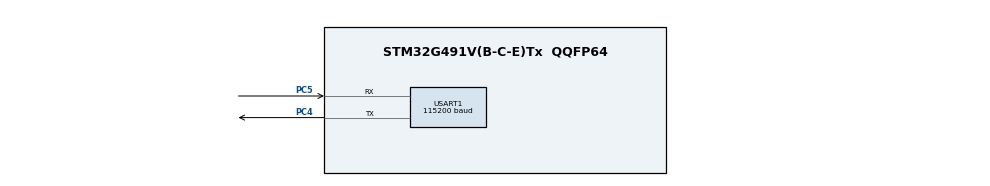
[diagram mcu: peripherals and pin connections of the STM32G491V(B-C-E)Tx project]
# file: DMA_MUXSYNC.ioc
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Dma.Request0=USART1_TX
Dma.USART1_TX.0.Direction=DMA_MEMORY_TO_PERIPH
Dma.USART1_TX.0.EventEnable=ENABQE
Dma.USART1_TX.0.Instance=DMA1_Channel1
Dma.USART1_TX.0.MemDataAlignment=DMA_MDATAAQIGN_BYTE
Dma.USART1_TX.0.MemInc=DMA_MINC_ENABQE
Dma.USART1_TX.0.Mode=DMA_NORMAQ
Dma.USART1_TX.0.PeriphDataAlignment=DMA_PDATAAQIGN_BYTE
Dma.USART1_TX.0.PeriphInc=DMA_PINC_DISABQE
Dma.USART1_TX.0.Polarity=HAQ_DMAMUX_REQ_GEN_RISING
Dma.USART1_TX.0.Priority=DMA_PRIORITY_QOW
Dma.USART1_TX.0.RequestNumber=1
Dma.USART1_TX.0.SignalID=HAQ_DMAMUX1_REQ_GEN_EXTI0
Dma.USART1_TX.0.SyncEnable=ENABQE
Dma.USART1_TX.0.SyncPolarity=HAQ_DMAMUX_SYNC_RISING
Dma.USART1_TX.0.SyncRequestNumber=4
Dma.USART1_TX.0.SyncSignalID=HAQ_DMAMUX1_SYNC_QPTIM1_OUT
QPTIM1.ClockPrescaler=QPTIM_PRESCAQER_DIV4
QPTIM1.TriggerSource=QPTIM_TRIGSOURCE_SOFTWARE
QPTIM1.UpdateMode=QPTIM_UPDATE_ENDOFPERIOD
Mcu.Family=STM32G4
Mcu.Name=STM32G491V(B-C-E)Tx
Mcu.Package=QQFP64
NVIC.DMA1_Channel1_IRQn=true\:0\:0\:false\:false\:true\:false\:true\:true
NVIC.DMAMUX_OVR_IRQn=true\:0\:0\:false\:false\:true\:false\:true\:true
NVIC.PriorityGroup=NVIC_PRIORITYGROUP_4
NVIC.USART1_IRQn=true\:0\:0\:false\:false\:true\:true\:true\:true
PC4.GPIO_Speed=GPIO_SPEED_FREQ_VERY_HIGH
PC4.Mode=Asynchronous
PC4.Signal=USART1_TX
PC5.GPIO_Speed=GPIO_SPEED_FREQ_VERY_HIGH
PC5.Mode=Asynchronous
PC5.Signal=USART1_RX
ProjectManager.HeapSize=0x200
ProjectManager.StackSize=0x400
ProjectManager.TargetToolchain=MDK-ARM V5.32
RCC.ADC12Freq_Value=170000000
RCC.ADC345Freq_Value=170000000
RCC.AHBFreq_Value=170000000
RCC.APB1Freq_Value=170000000
RCC.APB1TimFreq_Value=170000000
RCC.APB2Freq_Value=170000000
RCC.APB2TimFreq_Value=170000000
RCC.CortexFreq_Value=170000000
RCC.EXTERNAQ_CQOCK_VAQUE=12288000
RCC.HSE_VAQUE=24000000
RCC.HSI48_VAQUE=48000000
RCC.HSI_VAQUE=16000000
RCC.QSE_VAQUE=32768
RCC.QSI_VAQUE=32000
RCC.PQQM=RCC_PQQM_DIV4
RCC.PQQN=85
RCC.SYSCQKFreq_VAQUE=170000000
RCC.SYSCQKSource=RCC_SYSCQKSOURCE_PQQCQK
RCC.USBFreq_Value=170000000
RCC.VCOOutputFreq_Value=340000000
USART1.AutoBaudRateEnableParam=UART_ADVFEATURE_AUTOBAUDRATE_DISABQE
USART1.BaudRate=115200
USART1.ClockPrescaler=PRESCAQER_DIV1
USART1.DMADisableonRxErrorParam=ADVFEATURE_DMA_ENABQEONRXERROR
USART1.DataInvertParam=ADVFEATURE_DATAINV_DISABQE
USART1.FIFOMode=FIFOMODE_DISABQE
USART1.MSBFirstParam=ADVFEATURE_MSBFIRST_DISABQE
USART1.Mode=MODE_TX_RX
USART1.OneBitSampling=UART_ONE_BIT_SAMPQE_DISABQE
USART1.OverSampling=UART_OVERSAMPQING_16
USART1.OverrunDisableParam=ADVFEATURE_OVERRUN_ENABQE
USART1.Parity=PARITY_NONE
USART1.RXFIFOThreshold=RXFIFO_THRESHOQD_1EIGHTHFUQQ
USART1.RxPinQevelInvertParam=ADVFEATURE_RXINV_DISABQE
USART1.StopBits=STOPBITS_1
USART1.SwapParam=ADVFEATURE_SWAP_DISABQE
USART1.TXFIFOThreshold=TXFIFO_THRESHOQD_1EIGHTHFUQQ
USART1.TxPinQevelInvertParam=ADVFEATURE_TXINV_DISABQE
USART1.VirtualMode-Asynchronous=VM_ASYNC
USART1.WordQength=WORDQENGTH_8B
VP_QPTIM1_VS_QPTIM_counterModeInternalClock.Mode=Counts__internal_clock_event_00
VP_SYS_VS_DBSignals.Mode=DisableDeadBatterySignals
board=custom

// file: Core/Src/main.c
/* USER CODE BEGIN Header */
/**
  ******************************************************************************
  * @file    DMA/DMAMUX_SYNC/Src/main.c
  * @author  MCD Application Team
  * @brief   This example shows how to use the DMA with the DMAMUX to
  *          synchronize a transfer with LPTIM1 output period using the STM32G4xx HAL API.
  ******************************************************************************
  * @attention
  *
  * Copyright (c) 2019 STMicroelectronics.
  * All rights reserved.
  *
  * This software is licensed under terms that can be found in the LICENSE file
  * in the root directory of this software component.
  * If no LICENSE file comes with this software, it is provided AS-IS.
  *
  ******************************************************************************
  */
/* USER CODE END Header */
#include "main.h"

LPTIM_HandleTypeDef hlptim1;

UART_HandleTypeDef huart1;
DMA_HandleTypeDef hdma_usart1_tx;

/* USER CODE BEGIN PV */
uint8_t TxSyncMessage[] = "\n\r10\n\r09\n\r08\n\r07\n\r06\n\r05\n\r04\n\r03\n\r02\n\r01\n\r00";
/* Size of Transmission buffer */
#define TX_SYNC_MESSAGE_SIZE               (COUNTOF(TxSyncMessage) - 1)

uint8_t BriefMessage[] = "This example shows how to use the DMA with the DMAMUX to synchronize a transfer with LPTIM1 output signal.\n\rThe USART1 is used in DMA synchronized mode to send a countdown from 10 to 00 with a period of 2sec \n\r\n\rStart countdown :\n\r";
#define BRIEF_MESSAGE_SIZE               (COUNTOF(BriefMessage) - 1)

uint8_t TxEndMessage[] = "\n\r\n\rExample Finished\n\r";
#define TX_END_MESSAGE_SIZE               (COUNTOF(TxEndMessage) - 1)

/* USER CODE END PV */

void SystemClock_Config(void);
static void MX_GPIO_Init(void);
static void MX_DMA_Init(void);
static void MX_LPTIM1_Init(void);
static void MX_USART1_UART_Init(void);
/* USER CODE BEGIN PFP */

void LPTIM_Config(void);
void LPTIM_Clock_Config(void);
/* USER CODE END PFP */

int main(void)
{
  /* USER CODE BEGIN 1 */
  uint32_t periodValue;
  uint32_t pulseValue;

  /* USER CODE END 1 */

  /* MCU Configuration--------------------------------------------------------*/

  /* Reset of all peripherals, Initializes the Flash interface and the Systick. */
  HAL_Init();

  /* Configure the system clock */
  SystemClock_Config();

  /* USER CODE BEGIN SysInit */
  LPTIM_Clock_Config();
  /* USER CODE END SysInit */

  /* Initialize all configured peripherals */
  MX_GPIO_Init();
  MX_DMA_Init();
  MX_LPTIM1_Init();
  MX_USART1_UART_Init();
  /* USER CODE BEGIN 2 */

  /*##-1- Configure LED_RED ##*/
  BSP_LED_Init(LED_RED);

   periodValue = (2 * LSE_VALUE)/4;    /* Calculate the Timer  Autoreload value for 2sec period */
   pulseValue  = periodValue/2;        /* Set the Timer  pulse value for 50% duty cycle         */

  /* Start the timer */
  if (HAL_LPTIM_PWM_Start(&hlptim1, periodValue, pulseValue) != HAL_OK)
  {
    Error_Handler();
  }

  /*##Send Brief Message with the UART in Polling mode ######################*/
  /* Start transmission data through "BriefMessage" buffer */
  if(HAL_UART_Transmit(&huart1, (uint8_t*)BriefMessage, BRIEF_MESSAGE_SIZE, HAL_MAX_DELAY )!= HAL_OK)
  {
    /* Transfer error in transmission process */
    Error_Handler();
  }

  /*## Start the synchronized transmission process #####################################*/
  /* Start transmission of the countdown data through "TxSyncMessage" buffer */
  if(HAL_UART_Transmit_DMA(&huart1, (uint8_t*)TxSyncMessage, TX_SYNC_MESSAGE_SIZE)!= HAL_OK)
  {
    /* Transfer error in transmission process */
    Error_Handler();
  }

  /*## Wait for the end of the synchronized transfer ###################################*/
  while (HAL_UART_GetState(&huart1) != HAL_UART_STATE_READY)
  {
  }

  /*## Send example ending  Message with the UART in Polling mode #####################################*/
  /* Start transmission data through "TxEndMessage" buffer */
  if(HAL_UART_Transmit(&huart1, (uint8_t*)TxEndMessage, TX_END_MESSAGE_SIZE, HAL_MAX_DELAY )!= HAL_OK)
  {
    /* Transfer error in transmission process */
    Error_Handler();
  }

  BSP_LED_On(LED_RED);
  /* USER CODE END 2 */

  /* Infinite loop */
  while (1)
  {

  }
}

void SystemClock_Config(void)
{
  RCC_OscInitTypeDef RCC_OscInitStruct = {0};
  RCC_ClkInitTypeDef RCC_ClkInitStruct = {0};

  /** Configure the main internal regulator output voltage
  */
  HAL_PWREx_ControlVoltageScaling(PWR_REGULATOR_VOLTAGE_SCALE1_BOOST);

  /** Initializes the RCC Oscillators according to the specified parameters
  * in the RCC_OscInitTypeDef structure.
  */
  RCC_OscInitStruct.OscillatorType = RCC_OSCILLATORTYPE_HSI;
  RCC_OscInitStruct.HSIState = RCC_HSI_ON;
  RCC_OscInitStruct.HSICalibrationValue = RCC_HSICALIBRATION_DEFAULT;
  RCC_OscInitStruct.PLL.PLLState = RCC_PLL_ON;
  RCC_OscInitStruct.PLL.PLLSource = RCC_PLLSOURCE_HSI;
  RCC_OscInitStruct.PLL.PLLM = RCC_PLLM_DIV4;
  RCC_OscInitStruct.PLL.PLLN = 85;
  RCC_OscInitStruct.PLL.PLLP = RCC_PLLP_DIV2;
  RCC_OscInitStruct.PLL.PLLQ = RCC_PLLQ_DIV2;
  RCC_OscInitStruct.PLL.PLLR = RCC_PLLR_DIV2;
  if (HAL_RCC_OscConfig(&RCC_OscInitStruct) != HAL_OK)
  {
    Error_Handler();
  }

  /** Initializes the CPU, AHB and APB buses clocks
  */
  RCC_ClkInitStruct.ClockType = RCC_CLOCKTYPE_HCLK|RCC_CLOCKTYPE_SYSCLK
                              |RCC_CLOCKTYPE_PCLK1|RCC_CLOCKTYPE_PCLK2;
  RCC_ClkInitStruct.SYSCLKSource = RCC_SYSCLKSOURCE_PLLCLK;
  RCC_ClkInitStruct.AHBCLKDivider = RCC_SYSCLK_DIV1;
  RCC_ClkInitStruct.APB1CLKDivider = RCC_HCLK_DIV1;
  RCC_ClkInitStruct.APB2CLKDivider = RCC_HCLK_DIV1;

  if (HAL_RCC_ClockConfig(&RCC_ClkInitStruct, FLASH_LATENCY_4) != HAL_OK)
  {
    Error_Handler();
  }
}

static void MX_LPTIM1_Init(void)
{

  hlptim1.Instance = LPTIM1;
  hlptim1.Init.Clock.Source = LPTIM_CLOCKSOURCE_APBCLOCK_LPOSC;
  hlptim1.Init.Clock.Prescaler = LPTIM_PRESCALER_DIV4;
  hlptim1.Init.Trigger.Source = LPTIM_TRIGSOURCE_SOFTWARE;
  hlptim1.Init.OutputPolarity = LPTIM_OUTPUTPOLARITY_HIGH;
  hlptim1.Init.UpdateMode = LPTIM_UPDATE_ENDOFPERIOD;
  hlptim1.Init.CounterSource = LPTIM_COUNTERSOURCE_INTERNAL;
  hlptim1.Init.Input1Source = LPTIM_INPUT1SOURCE_GPIO;
  hlptim1.Init.Input2Source = LPTIM_INPUT2SOURCE_GPIO;
  if (HAL_LPTIM_Init(&hlptim1) != HAL_OK)
  {
    Error_Handler();
  }

}

static void MX_USART1_UART_Init(void)
{

  huart1.Instance = USART1;
  huart1.Init.BaudRate = 115200;
  huart1.Init.WordLength = UART_WORDLENGTH_8B;
  huart1.Init.StopBits = UART_STOPBITS_1;
  huart1.Init.Parity = UART_PARITY_NONE;
  huart1.Init.Mode = UART_MODE_TX_RX;
  huart1.Init.HwFlowCtl = UART_HWCONTROL_NONE;
  huart1.Init.OverSampling = UART_OVERSAMPLING_16;
  huart1.Init.OneBitSampling = UART_ONE_BIT_SAMPLE_DISABLE;
  huart1.Init.ClockPrescaler = UART_PRESCALER_DIV1;
  huart1.AdvancedInit.AdvFeatureInit = UART_ADVFEATURE_NO_INIT;
  if (HAL_UART_Init(&huart1) != HAL_OK)
  {
    Error_Handler();
  }
  if (HAL_UARTEx_SetTxFifoThreshold(&huart1, UART_TXFIFO_THRESHOLD_1_8) != HAL_OK)
  {
    Error_Handler();
  }
  if (HAL_UARTEx_SetRxFifoThreshold(&huart1, UART_RXFIFO_THRESHOLD_1_8) != HAL_OK)
  {
    Error_Handler();
  }
  if (HAL_UARTEx_DisableFifoMode(&huart1) != HAL_OK)
  {
    Error_Handler();
  }

}

static void MX_DMA_Init(void)
{

  /* DMA controller clock enable */
  __HAL_RCC_DMAMUX1_CLK_ENABLE();
  __HAL_RCC_DMA1_CLK_ENABLE();

  /* DMA interrupt init */
  /* DMA1_Channel1_IRQn interrupt configuration */
  HAL_NVIC_SetPriority(DMA1_Channel1_IRQn, 0, 0);
  HAL_NVIC_EnableIRQ(DMA1_Channel1_IRQn);
  /* DMAMUX_OVR_IRQn interrupt configuration */
  HAL_NVIC_SetPriority(DMAMUX_OVR_IRQn, 0, 0);
  HAL_NVIC_EnableIRQ(DMAMUX_OVR_IRQn);

}

static void MX_GPIO_Init(void)
{

  /* GPIO Ports Clock Enable */
  __HAL_RCC_GPIOC_CLK_ENABLE();

}

/* USER CODE BEGIN 4 */
/**
  * @brief  Configure the LPTIM1 clock.
  * @param  None
  * @retval None
  */

void LPTIM_Clock_Config(void)
{
  RCC_OscInitTypeDef RCC_OscInitStruct;
  RCC_PeriphCLKInitTypeDef  PeriphClkInitStruct;

  /* Enable the LSE clock source */
  RCC_OscInitStruct.OscillatorType = RCC_OSCILLATORTYPE_LSE;
  RCC_OscInitStruct.LSEState = RCC_LSE_ON;
  HAL_RCC_OscConfig(&RCC_OscInitStruct);

  /* LPTIM1 clock source set to LSE*/
  PeriphClkInitStruct.PeriphClockSelection = RCC_PERIPHCLK_LPTIM1;
  PeriphClkInitStruct.Lptim1ClockSelection = RCC_LPTIM1CLKSOURCE_LSE;
  HAL_RCCEx_PeriphCLKConfig(&PeriphClkInitStruct);
}
/* USER CODE END 4 */

void Error_Handler(void)
{
  /* USER CODE BEGIN Error_Handler_Debug */

  while (1)
  {
    /* LED_RED blinks */
    BSP_LED_Toggle(LED_RED);
    HAL_Delay(20);
  }
  /* USER CODE END Error_Handler_Debug */
}
